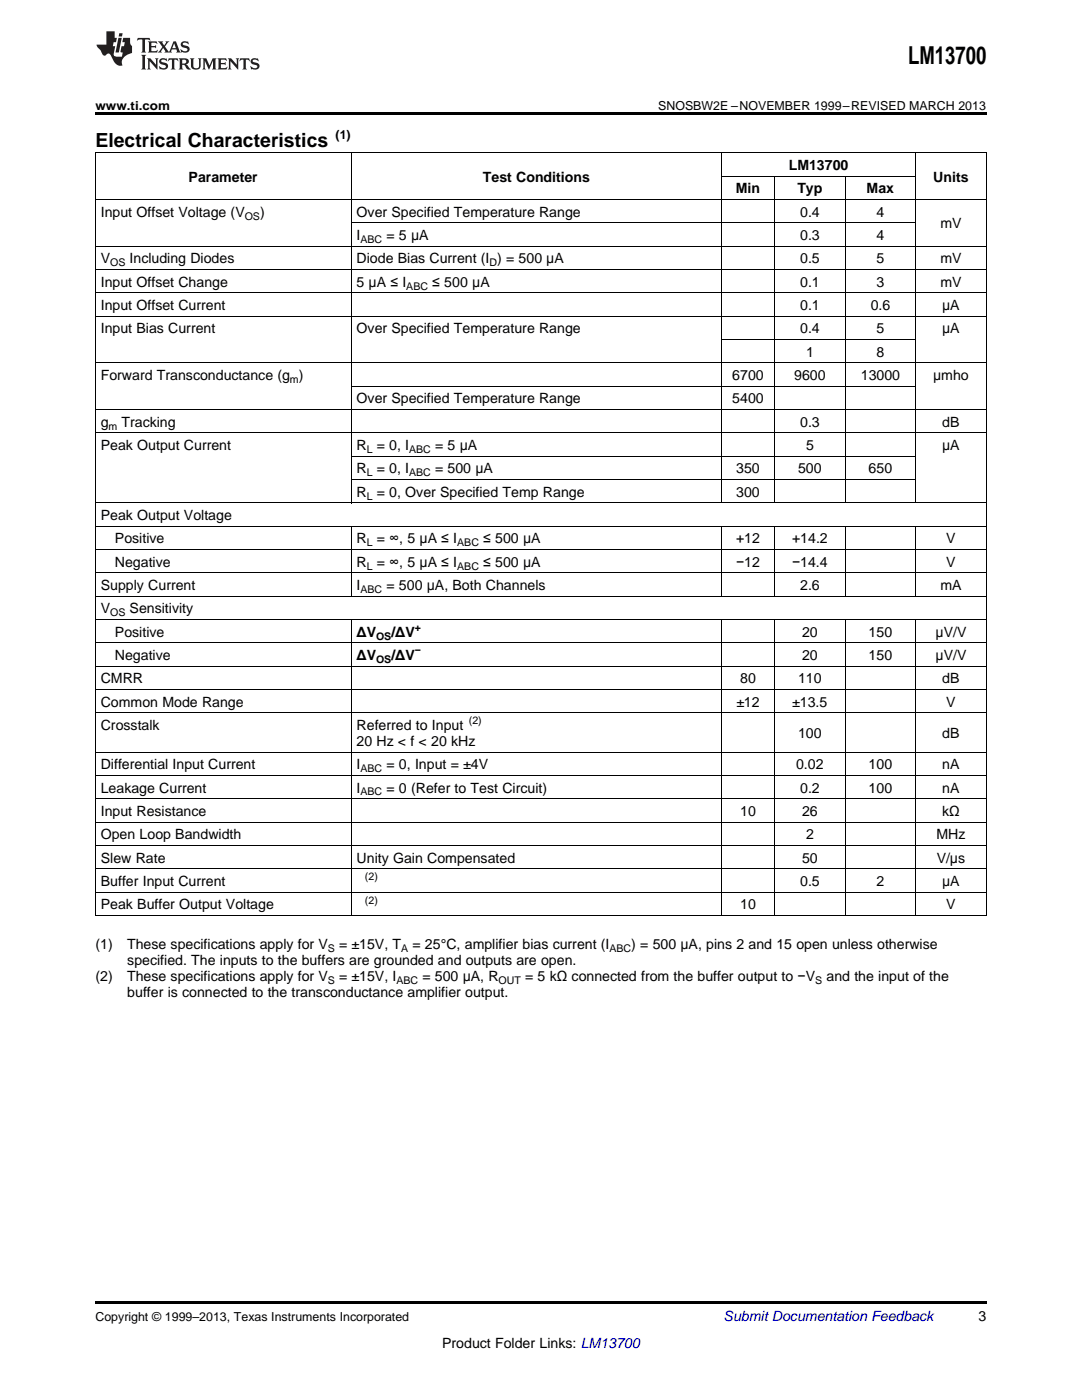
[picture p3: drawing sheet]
<svg xmlns="http://www.w3.org/2000/svg" width="216mm" height="279mm" viewBox="0 0 216 279" stroke-linecap="round" stroke-linejoin="round" font-family="sans-serif">
<defs><g id="words">
<text font-size="4.9" x="181.2" y="12.8">LM13700</text>
<text font-size="3.9" x="19" y="29.3">Electrical Characteristics</text>
<g font-size="2.8">
<text x="157.4" y="33.9">LM13700</text>
<text x="37.6" y="36.3">Parameter</text>
<text x="96.3" y="36.3">Test Conditions</text>
<text x="146.8" y="38.6">Min</text>
<text x="159.1" y="38.6">Typ</text>
<text x="172.9" y="38.6">Max</text>
<text x="186.2" y="36.3">Units</text>
<text x="20.1" y="43.3">Input Offset Voltage (V</text>
<text x="51.9" y="43.3">)</text>
<text x="71.2" y="43.3">Over Specified Temperature Range</text>
<text x="71.2" y="47.9">I</text>
<text x="77.1" y="47.9">= 5 μA</text>
<text x="159.7" y="43.3">0.4</text>
<text x="159.7" y="47.9">0.3</text>
<text x="174.9" y="43.3">4</text>
<text x="174.9" y="47.9">4</text>
<text x="187.6" y="45.6">mV</text>
<text x="20.1" y="52.6">V</text>
<text x="25.9" y="52.6">Including Diodes</text>
<text x="71.2" y="52.6">Diode Bias Current (I ) = 500 μA</text>
<text x="159.7" y="52.6">0.5</text>
<text x="174.9" y="52.6">5</text>
<text x="187.6" y="52.6">mV</text>
<text x="20.1" y="57.2">Input Offset Change</text>
<text x="71.2" y="57.2">5 μA ≤ I</text>
<text x="86.3" y="57.2">≤ 500 μA</text>
<text x="159.7" y="57.2">0.1</text>
<text x="174.9" y="57.2">3</text>
<text x="187.6" y="57.2">mV</text>
<text x="20.1" y="61.9">Input Offset Current</text>
<text x="159.7" y="61.9">0.1</text>
<text x="173.7" y="61.9">0.6</text>
<text x="188" y="61.9">μA</text>
<text x="20.1" y="66.5">Input Bias Current</text>
<text x="71.2" y="66.5">Over Specified Temperature Range</text>
<text x="159.7" y="66.5">0.4</text>
<text x="160.8" y="71.2">1</text>
<text x="174.9" y="66.5">5</text>
<text x="174.9" y="71.2">8</text>
<text x="188" y="66.5">μA</text>
<text x="20.1" y="75.8">Forward Transconductance (g )</text>
<text x="146.1" y="75.8">6700</text>
<text x="158.5" y="75.8">9600</text>
<text x="171.8" y="75.8">13000</text>
<text x="186.2" y="75.8">μmho</text>
<text x="71.2" y="80.5">Over Specified Temperature Range</text>
<text x="146.1" y="80.5">5400</text>
<text x="20.1" y="85.2">g</text>
<text x="20.1" y="89.8">Peak Output Current</text>
<text x="24.2" y="85.2">Tracking</text>
<text x="71.2" y="89.8">R</text>
<text x="75.2" y="89.8">= 0, I</text>
<text x="86.8" y="89.8">= 5 μA</text>
<text x="159.7" y="85.2">0.3</text>
<text x="160.8" y="89.8">5</text>
<text x="188" y="89.8">μA</text>
<text x="188" y="85.2">dB</text>
<text x="71.2" y="94.5">R</text>
<text x="75.2" y="94.5">= 0, I</text>
<text x="86.8" y="94.5">= 500 μA</text>
<text x="146.9" y="94.5">350</text>
<text x="159.2" y="94.5">500</text>
<text x="173.3" y="94.5">650</text>
<text x="71.2" y="99.1">R</text>
<text x="75.2" y="99.1">= 0, Over Specified Temp Range</text>
<text x="146.9" y="99.1">300</text>
<text x="20.1" y="103.8">Peak Output Voltage</text>
<text x="22.9" y="108.4">Positive</text>
<text x="22.9" y="113.1">Negative</text>
<text x="71.2" y="108.4">R</text>
<text x="71.2" y="113.1">R</text>
<text x="75.2" y="108.4">= ∞, 5 μA ≤ I</text>
<text x="75.2" y="113.1">= ∞, 5 μA ≤ I</text>
<text x="96.4" y="108.4">≤ 500 μA</text>
<text x="96.4" y="113.1">≤ 500 μA</text>
<text x="146.9" y="108.4">+12</text>
<text x="146.9" y="113.1">−12</text>
<text x="158" y="108.4">+14.2</text>
<text x="158" y="113.1">−14.4</text>
<text x="188.8" y="108.4">V</text>
<text x="188.8" y="113.1">V</text>
<text x="20.1" y="117.8">Supply Current</text>
<text x="71.2" y="117.8">I</text>
<text x="77.1" y="117.8">= 500 μA, Both Channels</text>
<text x="159.7" y="117.8">2.6</text>
<text x="187.6" y="117.8">mA</text>
<text x="20.1" y="122.4">V</text>
<text x="25.9" y="122.4">Sensitivity</text>
<text x="22.9" y="127.1">Positive</text>
<text x="22.9" y="131.7">Negative</text>
<text x="71.2" y="127.1">ΔV</text>
<text x="71.2" y="131.7">ΔV</text>
<text x="78.1" y="127.1">/ΔV</text>
<text x="78.1" y="131.7">/ΔV</text>
<text x="160.1" y="127.1">20</text>
<text x="160.1" y="131.7">20</text>
<text x="173.3" y="127.1">150</text>
<text x="173.3" y="131.7">150</text>
<text x="186.7" y="127.1">μV/V</text>
<text x="186.7" y="131.7">μV/V</text>
<text x="20.1" y="136.4">CMRR</text>
<text x="147.7" y="136.4">80</text>
<text x="159.2" y="136.4">110</text>
<text x="188" y="136.4">dB</text>
<text x="20.1" y="141">Common Mode Range</text>
<text x="146.9" y="141">±12</text>
<text x="158.1" y="141">±13.5</text>
<text x="188.8" y="141">V</text>
<text x="20.1" y="145.7">Crosstalk</text>
<text x="71.2" y="145.7">Referred to Input</text>
<text x="71.2" y="148.9">20 Hz &lt; f &lt; 20 kHz</text>
<text x="159.2" y="147.3">100</text>
<text x="188" y="147.3">dB</text>
<text x="20.1" y="153.5">Differential Input Current</text>
<text x="71.2" y="153.5">I</text>
<text x="77.1" y="153.5">= 0, Input = ±4V</text>
<text x="158.9" y="153.5">0.02</text>
<text x="173.3" y="153.5">100</text>
<text x="188" y="153.5">nA</text>
<text x="20.1" y="158.2">Leakage Current</text>
<text x="71.2" y="158.2">I</text>
<text x="77.1" y="158.2">= 0 (Refer to Test Circuit)</text>
<text x="159.7" y="158.2">0.2</text>
<text x="173.3" y="158.2">100</text>
<text x="188" y="158.2">nA</text>
<text x="20.1" y="162.8">Input Resistance</text>
<text x="20.1" y="167.5">Open Loop Bandwidth</text>
<text x="147.7" y="162.8">10</text>
<text x="160.1" y="162.8">26</text>
<text x="160.8" y="167.5">2</text>
<text x="186.9" y="167.5">MHz</text>
<text x="188" y="162.8">kΩ</text>
<text x="20.1" y="172.2">Slew Rate</text>
<text x="71.2" y="172.2">Unity Gain Compensated</text>
<text x="160.1" y="172.2">50</text>
<text x="186.9" y="172.2">V/μs</text>
<text x="20.1" y="176.8">Buffer Input Current</text>
<text x="159.7" y="176.8">0.5</text>
<text x="174.9" y="176.8">2</text>
<text x="188" y="176.8">μA</text>
<text x="20.1" y="181.5">Peak Buffer Output Voltage</text>
<text x="147.7" y="181.5">10</text>
<text x="188.8" y="181.5">V</text>
<text x="19" y="189.4">(1)</text>
<text x="25.4" y="189.4">These specifications apply for V</text>
<text x="67.7" y="189.4">= ±15V, T</text>
<text x="82.3" y="189.4">= 25°C, amplifier bias current (I</text>
<text x="126" y="189.4">) = 500 μA, pins 2 and 15 open unless otherwise</text>
<text x="19" y="195.8">(2)</text>
<text x="25.4" y="195.8">These specifications apply for V</text>
<text x="25.4" y="192.6">specified. The inputs to the buffers are grounded and outputs are open.</text>
<text x="67.7" y="195.8">= ±15V, I</text>
<text x="84.3" y="195.8">= 500 μA, R</text>
<text x="104.8" y="195.8">= 5 kΩ connected from the buffer output to −V</text>
<text x="164.9" y="195.8">and the input of the</text>
<text x="25.4" y="199">buffer is connected to the transconductance amplifier output.</text>
<text x="195.3" y="263.6">3</text>
<text x="88.2" y="269">Product Folder Links: LM13700</text>
</g>
<text font-size="2.8" fill="#0000c8" x="144.4" y="263.6">Submit Documentation Feedback</text>
<g font-size="2.5">
<text x="19" y="21.9">www.ti.com</text>
<text x="131.3" y="21.9">SNOSBW2E –NOVEMBER 1999–REVISED MARCH 2013</text>
<text x="67" y="27.7">(1)</text>
<text x="19" y="263.6">Copyright © 1999–2013, Texas Instruments Incorporated</text>
</g>
<g font-size="2.1">
<text x="48.8" y="43.8">OS</text>
<text x="22" y="53.1">OS</text>
<text x="71.9" y="48.5">ABC</text>
<text x="97.7" y="53.1">D</text>
<text x="81.1" y="57.8">ABC</text>
<text x="57.9" y="76.4">m</text>
<text x="21.7" y="85.7">m</text>
<text x="73.2" y="90.4">L</text>
<text x="73.2" y="95">L</text>
<text x="81.6" y="90.4">ABC</text>
<text x="81.6" y="95">ABC</text>
<text x="73.2" y="99.7">L</text>
<text x="73.2" y="109">L</text>
<text x="73.2" y="113.7">L</text>
<text x="91.2" y="109">ABC</text>
<text x="91.2" y="113.7">ABC</text>
<text x="71.9" y="118.3">ABC</text>
<text x="22" y="123">OS</text>
<text x="82.8" y="125.9">+</text>
<text x="75" y="127.6">OS</text>
<text x="82.8" y="130.6">−</text>
<text x="75" y="132.3">OS</text>
<text x="93.5" y="144.6">(2)</text>
<text x="71.9" y="154.1">ABC</text>
<text x="71.9" y="158.8">ABC</text>
<text x="72.8" y="175.7">(2)</text>
<text x="72.8" y="180.3">(2)</text>
<text x="65.4" y="190">S</text>
<text x="80" y="190">A</text>
<text x="121.6" y="190">ABC</text>
<text x="65.4" y="196.4">S</text>
<text x="79.1" y="196.4">ABC</text>
<text x="99.5" y="196.4">OUT</text>
<text x="162.7" y="196.4">S</text>
</g>
</g></defs>
<path d="M19 22.5h177.8v.5h-177.8zM19 259.7h177.8v.5h-177.8z" fill="#000"/>
<g fill="none" stroke="#000" stroke-width=".2">
<path d="M19 39.8h177.8M19 30.5h177.8M19.1 30.6v152.1M70 30.6v69.8M144 30.6v69.8M144 35.2h38.7M154.5 35.2v65.2M168.6 35.2v65.2M182.7 30.6v69.8M196.8 30.6v152.1M19 58.4h177.8M19 53.8h177.8"/>
<path d="M19 49.1h177.8M70.1 44.5h112.6M19 72.4h177.8M19 63.1h177.8M70.1 77.1h112.6M144 67.8h38.7M19 86.4h177.8M19 81.7h177.8M70.1 95.7h112.6M70.1 91h112.6M19 119h177.8M19 114.3h177.8"/>
<path d="M19 109.7h177.8M19 105h177.8M19 100.3h177.8M70 105.1v13.9M144 105.1v13.9M154.5 105.1v13.9M168.6 105.1v13.9M182.7 105.1v13.9M19 137.6h177.8M19 132.9h177.8M19 128.3h177.8M19 123.6h177.8"/>
<path d="M70 123.7v59M144 123.7v59M154.5 123.7v59M168.6 123.7v59M182.7 123.7v59M19 159.4h177.8M19 154.7h177.8M19 150.1h177.8M19 142.3h177.8M19 178h177.8M19 173.4h177.8M19 168.7h177.8"/>
<path d="M19 164.1h177.8M19 182.7h177.8"/>
</g>
<g fill="#231f20">
<path d="M27.5 7.6l-.1 .5 .4-.2h.6v.1v2.1l-.2 .4h1l-.3-.4v-2.1l.1-.1h.5l.5 .2-.2-.5zM29.5 8.3l.2 .3v1.5l-.2 .4h1.8l.2-.6a1.04 1.04 0 0 1-1.3 .2v-.7h.6l.3 .2v-.6l-.3 .2h-.6v-.6l.8-.1 .4 .3-.2-.5zM31.5 8.3l.9 1.1-.9 1.1h.8l-.2-.2 .5-.7 .4 .7-.2 .2h1.5l-.1-.2 .1-.4h.9l.1 .4-.2 .2h1l-.3-.3-.7-1.9h-.5l-.9 2-.8-1 .9-1h-.8l.1 .3-.3 .5-.4-.6 .2-.2zM34.7 8.6l.4 1h-.7zM36.3 8.4a.63 .63 0 0 0-.2 .7 .63 .63 0 0 0 .6 .4l.6 .2 .1 .2a.75 .75 0 0 1-.7 .4 .75 .75 0 0 1-.6-.5l.1 .7 .1-.1a1.11 1.11 0 0 0 1.5-.6 1.13 1.13 0 0 0-1.2-.8l-.1-.4a1.04 1.04 0 0 1 1.2 .2l-.2-.5-.1 .1-.5-.2zM28.2 10.9l.2 .4v2.2l-.2 .4h1l-.3-.4v-2.2l.3-.4zM29.3 11.6l.3 .4v1.5l-.3 .4h.8l-.2-.4v-1.3l1.5 1.7v-1.9l.2-.4h-.7l.2 .4v.9l-1.1-1.3zM32 11.8a.62 .62 0 0 0-.2 .7 .62 .62 0 0 0 .6 .4l.6 .1 .1 .3a.76 .76 0 0 1-.7 .3 .76 .76 0 0 1-.6-.4l.1 .7 .1-.1a1.11 1.11 0 0 0 1.5-.6 1.13 1.13 0 0 0-1.2-.8l-.1-.4a1.04 1.04 0 0 1 1.2 .2l-.2-.6-.1 .1-.5-.1zM33.7 11.6l-.2 .6a.61 .61 0 0 1 .8-.3v1.6l-.2 .4h.9l-.2-.4v-1.6a.63 .63 0 0 1 .8 .3l-.2-.6zM35.6 11.6l.3 .4v1.5l-.3 .4h1l-.2-.2v-.8l.5 .2a.76 .76 0 0 0 1.2 .7l-1-1a.58 .58 0 0 0 .6-.5 .58 .58 0 0 0-.5-.6zM36.4 11.9h.1a.45 .45 0 0 1 .5 .1 .45 .45 0 0 1 .1 .5l-.7 .2zM37.9 11.6l.2 .2a2.17 2.17 0 0 0 .3 1.9 .99 .99 0 0 0 1.6-.6v-1.1l.2-.4h-.7l.2 .2a1.92 1.92 0 0 1-.2 1.8 .6 .6 0 0 1-.9-.5v-1.1l.2-.4zM40.4 11.6l.2 .4v1.5l-.2 .4h.7l-.2-.4v-1.4l.8 1.8 .8-1.8v1.4l-.2 .4h.9l-.2-.4v-1.5l.2-.4h-.8l-.6 1.5-.6-1.5zM43.4 11.6l.2 .4v1.5l-.2 .4h1.8l.2-.6a1.04 1.04 0 0 1-1.3 .1v-.6h.5l.4 .2v-.6l-.4 .2h-.5v-.7h.8l.3 .3-.1-.6zM45.5 11.6l.2 .4v1.5l-.2 .4h.7l-.2-.4v-1.3l1.5 1.7v-1.9l.2-.4h-.7l.2 .4v.9l-1.1-1.3zM47.9 11.6l-.1 .6a.61 .61 0 0 1 .8-.3v1.6l-.3 .4h1l-.3-.4 .1-1.6a.63 .63 0 0 1 .7 .3l-.1-.6zM50.2 11.8a.62 .62 0 0 0-.2 .7 .62 .62 0 0 0 .6 .4l.6 .1 .2 .3a.76 .76 0 0 1-.8 .3 .76 .76 0 0 1-.6-.4l.1 .7 .2-.1a1.11 1.11 0 0 0 1.5-.6 1.13 1.13 0 0 0-1.3-.8l-.1-.4a1.04 1.04 0 0 1 1.2 .2l-.1-.6-.2 .1-.5-.1z"/>
<path d="M21.2 6.3v2.6h-1.9l.1 .4 .7 .9a.91 .91 0 0 0 1 .8 .56 .56 0 0 1 .5-.3 .56 .56 0 0 1 .5 .3l.4 .8a1.53 1.53 0 0 0 1.9 1.2 1.54 1.54 0 0 1 1-2.1l.9-.3v-1.4a1.52 1.52 0 0 1-.3-1.6h-1.4l-.2 .8h.5l-.2 .8h-.4l-.2 1v.2l.4 .1-.2 .8a1.93 1.93 0 0 1-1.6-.3l.3-1.8h-.5l.2-.8h.4l.2-.8h-.4v-1.3zM23.6 7.6l-.6 2.9h.7l.6-2.9zM23.8 6.6l-.1 .7h.6l.2-.7z"/>
</g>
<use href="#words"/>
</svg>
